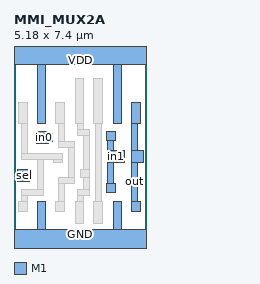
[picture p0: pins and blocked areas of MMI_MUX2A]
MACRO MMI_MUX2A
	CLASS CORE ;
	FOREIGN MMI_MUX2A 0 0 ;
	SIZE 5.18 BY 7.4 ;
	SYMMETRY X Y ;
	SITE CORE1 ;
	PIN out
		DIRECTION output ;
		USE SIGNAL ;
		PORT
			LAYER M1 ;
			RECT 4.58 4.6 4.92 5.44 ;
			LAYER M1 ;
			RECT 4.58 3.555 4.81 4.6 ;
			LAYER M1 ;
			RECT 4.58 3.105 5.035 3.555 ;
			LAYER M1 ;
			RECT 4.58 1.57 4.81 3.105 ;
			LAYER M1 ;
			RECT 4.58 1.19 4.92 1.57 ;
		END
		AntennaDiffArea 0.6624 ;
	END out
	PIN sel
		DIRECTION input ;
		USE SIGNAL ;
		PORT
			LAYER M1 ;
			RECT 0.145 2.365 0.595 2.815 ;
		END
		AntennaGateArea 0.5796 ;
	END sel
	PIN in1
		DIRECTION input ;
		USE SIGNAL ;
		PORT
			LAYER M1 ;
			RECT 3.62 3.945 3.96 4.285 ;
			LAYER M1 ;
			RECT 3.65 3.555 3.88 3.945 ;
			LAYER M1 ;
			RECT 3.65 3.105 4.295 3.555 ;
			LAYER M1 ;
			RECT 3.65 2.28 3.88 3.105 ;
			LAYER M1 ;
			RECT 3.62 1.94 3.96 2.28 ;
		END
		AntennaGateArea 0.2484 ;
	END in1
	PIN GND
		DIRECTION inout ;
		USE GROUND ;
		PORT
			LAYER M1 ;
			RECT 0.9 0.5 1.24 1.57 ;
			LAYER M1 ;
			RECT 3.86 0.5 4.2 1.57 ;
			LAYER M1 ;
			RECT 0 -0.5 5.18 0.5 ;
		END
	END GND
	PIN VDD
		DIRECTION inout ;
		USE POWER ;
		PORT
			LAYER M1 ;
			RECT 0 6.9 5.18 7.9 ;
			LAYER M1 ;
			RECT 0.9 4.6 1.24 6.9 ;
			LAYER M1 ;
			RECT 3.86 4.6 4.2 6.9 ;
		END
	END VDD
	PIN in0
		DIRECTION input ;
		USE SIGNAL ;
		PORT
			LAYER M1 ;
			RECT 0.885 4.245 1.335 4.295 ;
			LAYER M1 ;
			RECT 0.885 3.905 1.48 4.245 ;
			LAYER M1 ;
			RECT 0.885 3.845 1.335 3.905 ;
		END
		AntennaGateArea 0.2484 ;
	END in0
	OBS
		LAYER M1 ;
		RECT 0.18 4.6 0.52 5.44 ;
		LAYER M1 ;
		RECT 1.62 4.6 1.96 5.44 ;
		LAYER M1 ;
		RECT 2.38 4.6 2.72 6.36 ;
		LAYER M1 ;
		RECT 3.1 4.6 3.44 6.36 ;
		LAYER M1 ;
		RECT 0.29 3.44 0.52 4.6 ;
		LAYER M1 ;
		RECT 1.73 3.91 1.96 4.6 ;
		LAYER M1 ;
		RECT 2.49 4.37 2.72 4.6 ;
		LAYER M1 ;
		RECT 2.49 4.14 2.925 4.37 ;
		LAYER M1 ;
		RECT 1.73 3.68 2.35 3.91 ;
		LAYER M1 ;
		RECT 0.29 3.21 1.89 3.44 ;
		LAYER M1 ;
		RECT 0.925 2.045 1.155 3.21 ;
		LAYER M1 ;
		RECT 1.55 3.1 1.89 3.21 ;
		LAYER M1 ;
		RECT 2.12 2.495 2.35 3.68 ;
		LAYER M1 ;
		RECT 2.695 2.835 2.925 4.14 ;
		LAYER M1 ;
		RECT 2.59 2.495 2.93 2.835 ;
		LAYER M1 ;
		RECT 0.29 1.815 1.155 2.045 ;
		LAYER M1 ;
		RECT 1.73 2.265 2.35 2.495 ;
		LAYER M1 ;
		RECT 0.29 1.57 0.52 1.815 ;
		LAYER M1 ;
		RECT 1.73 1.57 1.96 2.265 ;
		LAYER M1 ;
		RECT 2.695 2.03 2.925 2.495 ;
		LAYER M1 ;
		RECT 2.49 1.8 2.925 2.03 ;
		LAYER M1 ;
		RECT 2.49 1.57 2.72 1.8 ;
		LAYER M1 ;
		RECT 3.16 1.57 3.39 4.6 ;
		LAYER M1 ;
		RECT 0.18 1.19 0.52 1.57 ;
		LAYER M1 ;
		RECT 1.62 1.19 1.96 1.57 ;
		LAYER M1 ;
		RECT 2.38 0.73 2.72 1.57 ;
		LAYER M1 ;
		RECT 3.1 0.73 3.44 1.57 ;
	END
END MMI_MUX2A
